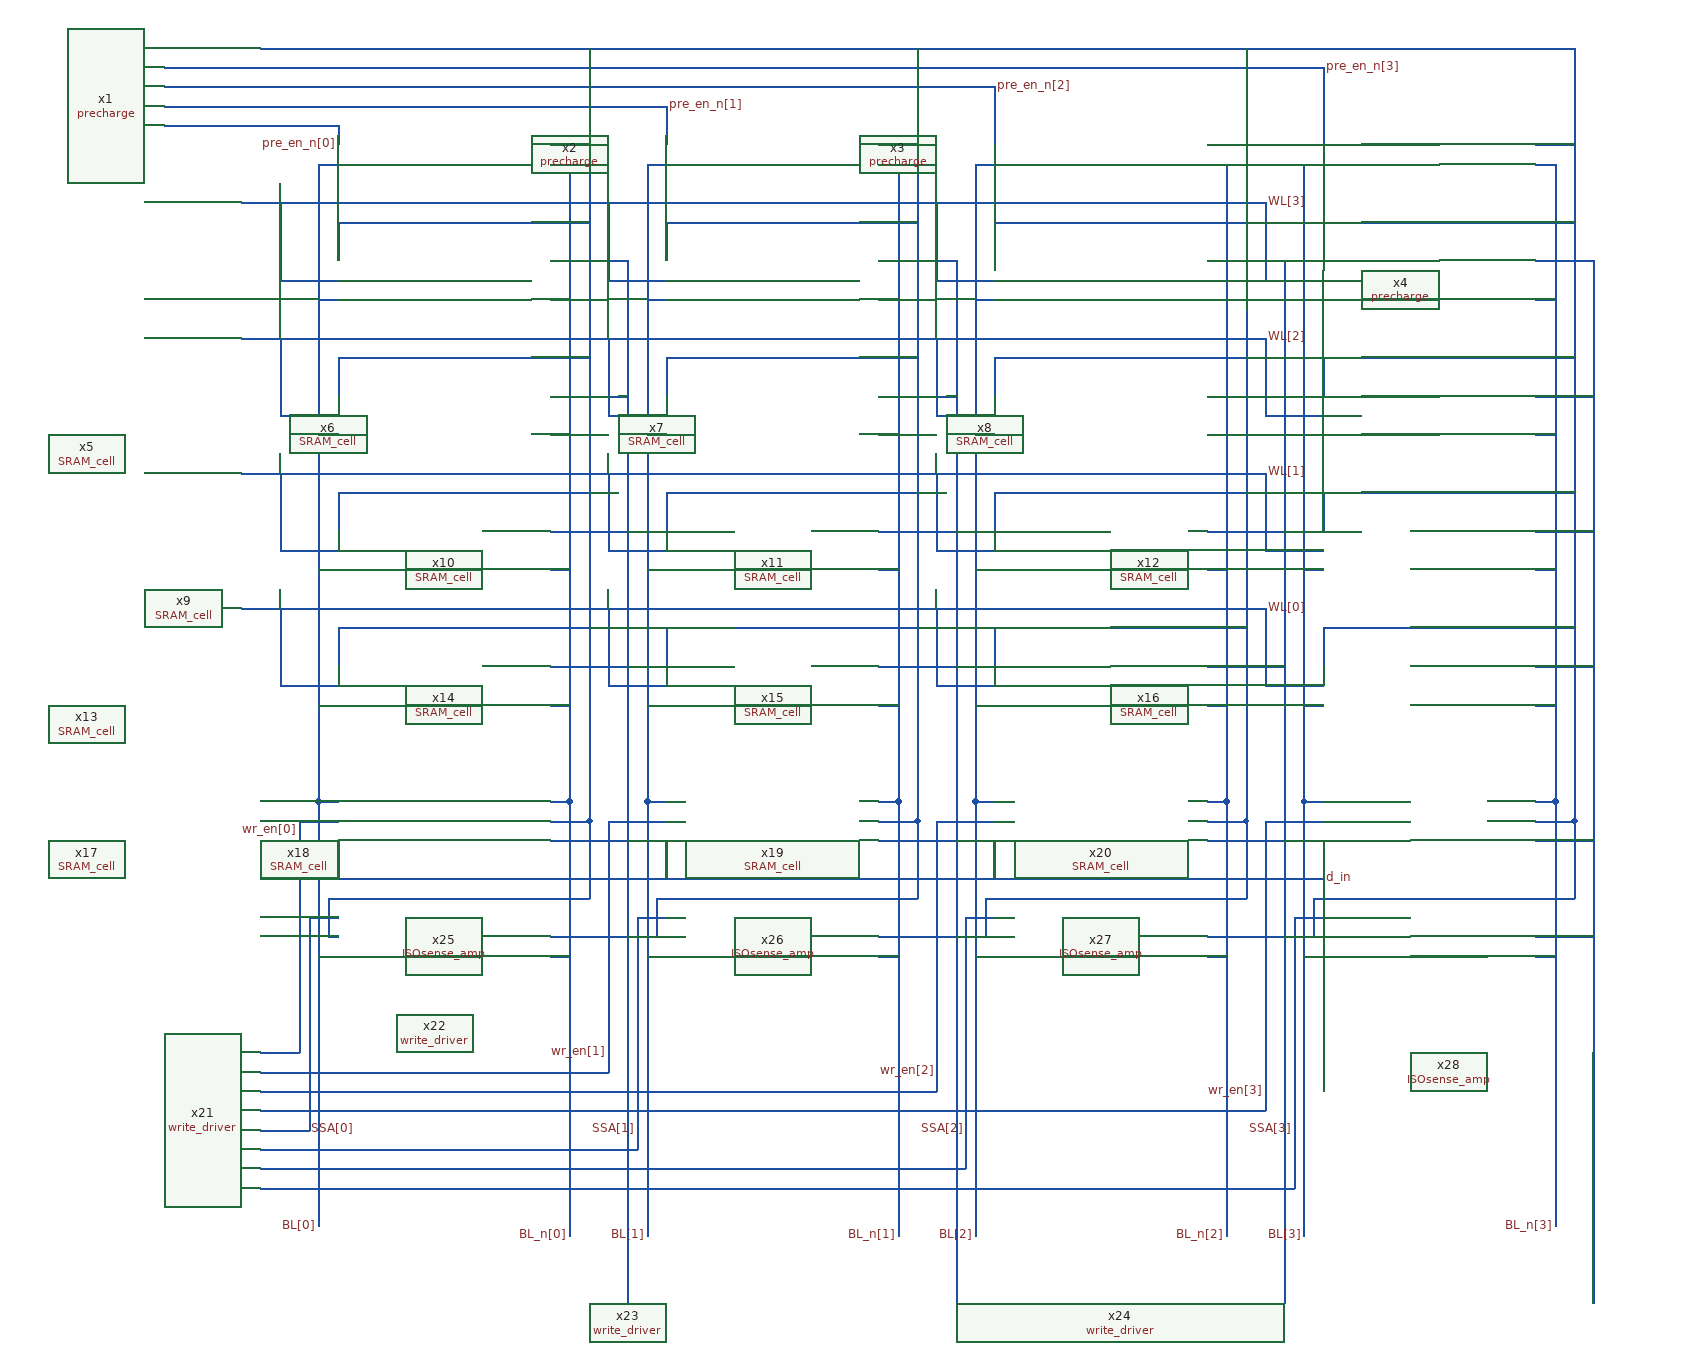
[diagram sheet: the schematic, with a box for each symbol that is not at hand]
v {xschem version=3.4.4 file_version=1.2
}
G {}
K {}
V {}
S {}
E {}
N 360 -1060 380 -1060 {
lab=BL[0]}
N 360 -920 380 -920 {
lab=BL[0]}
N 360 -780 380 -780 {
lab=BL[0]}
N 360 -640 380 -640 {
lab=BL[0]}
N 360 -500 380 -500 {
lab=BL[0]}
N 360 -400 380 -400 {
lab=BL[0]}
N 360 -1060 360 -400 {
lab=BL[0]}
N 600 -1060 620 -1060 {
lab=BL_n[0]}
N 600 -920 620 -920 {
lab=BL_n[0]}
N 600 -780 620 -780 {
lab=BL_n[0]}
N 600 -640 620 -640 {
lab=BL_n[0]}
N 600 -500 620 -500 {
lab=BL_n[0]}
N 600 -400 620 -400 {
lab=BL_n[0]}
N 620 -1060 620 -400 {
lab=BL_n[0]}
N 700 -1060 720 -1060 {
lab=BL[1]}
N 700 -920 720 -920 {
lab=BL[1]}
N 700 -780 720 -780 {
lab=BL[1]}
N 700 -640 720 -640 {
lab=BL[1]}
N 700 -500 720 -500 {
lab=BL[1]}
N 700 -400 720 -400 {
lab=BL[1]}
N 700 -1060 700 -400 {
lab=BL[1]}
N 1040 -1060 1060 -1060 {
lab=BL[2]}
N 1040 -920 1060 -920 {
lab=BL[2]}
N 1040 -780 1060 -780 {
lab=BL[2]}
N 1040 -640 1060 -640 {
lab=BL[2]}
N 1040 -500 1060 -500 {
lab=BL[2]}
N 1040 -400 1060 -400 {
lab=BL[2]}
N 1040 -1060 1040 -400 {
lab=BL[2]}
N 1380 -1060 1400 -1060 {
lab=BL[3]}
N 1380 -920 1400 -920 {
lab=BL[3]}
N 1380 -780 1400 -780 {
lab=BL[3]}
N 1380 -640 1400 -640 {
lab=BL[3]}
N 1380 -500 1400 -500 {
lab=BL[3]}
N 1380 -400 1400 -400 {
lab=BL[3]}
N 1380 -1060 1380 -400 {
lab=BL[3]}
N 940 -1060 960 -1060 {
lab=BL_n[1]}
N 940 -920 960 -920 {
lab=BL_n[1]}
N 940 -780 960 -780 {
lab=BL_n[1]}
N 940 -640 960 -640 {
lab=BL_n[1]}
N 940 -500 960 -500 {
lab=BL_n[1]}
N 940 -400 960 -400 {
lab=BL_n[1]}
N 960 -1060 960 -400 {
lab=BL_n[1]}
N 1280 -1060 1300 -1060 {
lab=BL_n[2]}
N 1280 -920 1300 -920 {
lab=BL_n[2]}
N 1280 -780 1300 -780 {
lab=BL_n[2]}
N 1280 -640 1300 -640 {
lab=BL_n[2]}
N 1280 -500 1300 -500 {
lab=BL_n[2]}
N 1280 -400 1300 -400 {
lab=BL_n[2]}
N 1300 -1060 1300 -400 {
lab=BL_n[2]}
N 1620 -1060 1640 -1060 {
lab=BL_n[3]}
N 1620 -920 1640 -920 {
lab=BL_n[3]}
N 1620 -780 1640 -780 {
lab=BL_n[3]}
N 1620 -640 1640 -640 {
lab=BL_n[3]}
N 1620 -500 1640 -500 {
lab=BL_n[3]}
N 1620 -400 1640 -400 {
lab=BL_n[3]}
N 1640 -1060 1640 -400 {
lab=BL_n[3]}
N 300 -1180 1660 -1180 {
lab=#net1}
N 600 -960 680 -960 {
lab=#net2}
N 600 -820 680 -820 {
lab=#net2}
N 600 -680 680 -680 {
lab=#net2}
N 600 -540 680 -540 {
lab=#net2}
N 600 -360 680 -360 {
lab=#net2}
N 600 -380 640 -380 {
lab=#net1}
N 600 -1080 640 -1080 {
lab=#net1}
N 380 -1000 380 -960 {
lab=#net1}
N 380 -1000 640 -1000 {
lab=#net1}
N 380 -860 380 -820 {
lab=#net1}
N 380 -860 640 -860 {
lab=#net1}
N 380 -720 380 -680 {
lab=#net1}
N 380 -720 640 -720 {
lab=#net1}
N 380 -580 380 -540 {
lab=#net1}
N 380 -580 640 -580 {
lab=#net1}
N 940 -380 980 -380 {
lab=#net1}
N 940 -1080 980 -1080 {
lab=#net1}
N 940 -960 1020 -960 {
lab=#net3}
N 940 -820 1020 -820 {
lab=#net3}
N 940 -680 1020 -680 {
lab=#net3}
N 940 -540 1020 -540 {
lab=#net3}
N 940 -360 1020 -360 {
lab=#net3}
N 720 -580 720 -540 {
lab=#net1}
N 720 -580 980 -580 {
lab=#net1}
N 720 -720 980 -720 {
lab=#net1}
N 720 -860 720 -820 {
lab=#net1}
N 720 -860 980 -860 {
lab=#net1}
N 720 -1000 720 -960 {
lab=#net1}
N 720 -1000 980 -1000 {
lab=#net1}
N 1280 -380 1320 -380 {
lab=#net1}
N 1280 -1080 1320 -1080 {
lab=#net1}
N 1280 -960 1360 -960 {
lab=#net4}
N 1280 -820 1360 -820 {
lab=#net4}
N 1280 -680 1360 -680 {
lab=#net4}
N 1280 -540 1360 -540 {
lab=#net4}
N 1280 -360 1360 -360 {
lab=#net4}
N 1620 -380 1660 -380 {
lab=#net1}
N 1620 -1080 1660 -1080 {
lab=#net1}
N 1060 -1000 1060 -960 {
lab=#net1}
N 1060 -1000 1320 -1000 {
lab=#net1}
N 1060 -860 1060 -820 {
lab=#net1}
N 1060 -860 1320 -860 {
lab=#net1}
N 1060 -720 1060 -680 {
lab=#net1}
N 1060 -720 1320 -720 {
lab=#net1}
N 1060 -580 1060 -540 {
lab=#net1}
N 1060 -580 1320 -580 {
lab=#net1}
N 1620 -960 1680 -960 {
lab=#net5}
N 1620 -820 1680 -820 {
lab=#net5}
N 1620 -680 1680 -680 {
lab=#net5}
N 1620 -540 1680 -540 {
lab=#net5}
N 1620 -360 1680 -360 {
lab=#net5}
N 1400 -580 1400 -540 {
lab=#net1}
N 1400 -580 1660 -580 {
lab=#net1}
N 1400 -720 1400 -680 {
lab=#net1}
N 1400 -720 1660 -720 {
lab=#net1}
N 1400 -860 1400 -820 {
lab=#net1}
N 1400 -860 1660 -860 {
lab=#net1}
N 1400 -1000 1400 -960 {
lab=#net1}
N 1400 -1000 1660 -1000 {
lab=#net1}
N 660 -660 720 -660 {
lab=WL[1]}
N 660 -740 660 -660 {
lab=WL[1]}
N 320 -660 380 -660 {
lab=WL[1]}
N 320 -740 320 -660 {
lab=WL[1]}
N 720 -720 720 -680 {
lab=#net1}
N 1000 -660 1060 -660 {
lab=WL[1]}
N 1000 -740 1000 -660 {
lab=WL[1]}
N 1340 -660 1400 -660 {
lab=WL[1]}
N 1340 -740 1340 -660 {
lab=WL[1]}
N 1340 -520 1400 -520 {
lab=WL[0]}
N 1340 -600 1340 -520 {
lab=WL[0]}
N 1000 -520 1060 -520 {
lab=WL[0]}
N 1000 -600 1000 -520 {
lab=WL[0]}
N 660 -520 720 -520 {
lab=WL[0]}
N 660 -600 660 -520 {
lab=WL[0]}
N 320 -520 380 -520 {
lab=WL[0]}
N 320 -600 320 -520 {
lab=WL[0]}
N 320 -940 380 -940 {
lab=WL[3]}
N 320 -1020 320 -940 {
lab=WL[3]}
N 660 -940 720 -940 {
lab=WL[3]}
N 660 -1020 660 -940 {
lab=WL[3]}
N 1000 -940 1060 -940 {
lab=WL[3]}
N 1000 -1020 1000 -940 {
lab=WL[3]}
N 1340 -940 1400 -940 {
lab=WL[3]}
N 1340 -1020 1340 -940 {
lab=WL[3]}
N 320 -800 380 -800 {
lab=WL[2]}
N 320 -880 320 -800 {
lab=WL[2]}
N 660 -800 720 -800 {
lab=WL[2]}
N 660 -880 660 -800 {
lab=WL[2]}
N 1000 -800 1060 -800 {
lab=WL[2]}
N 1000 -880 1000 -800 {
lab=WL[2]}
N 1340 -800 1400 -800 {
lab=WL[2]}
N 1340 -880 1340 -800 {
lab=WL[2]}
N 280 -1020 1340 -1020 {
lab=WL[3]}
N 280 -880 1340 -880 {
lab=WL[2]}
N 280 -740 1340 -740 {
lab=WL[1]}
N 280 -600 1340 -600 {
lab=WL[0]}
N 720 -1120 720 -1080 {
lab=pre_en_n[1]}
N 200 -1120 720 -1120 {
lab=pre_en_n[1]}
N 380 -1100 380 -1080 {
lab=pre_en_n[0]}
N 200 -1100 380 -1100 {
lab=pre_en_n[0]}
N 1060 -1140 1060 -1080 {
lab=pre_en_n[2]}
N 200 -1140 1060 -1140 {
lab=pre_en_n[2]}
N 1400 -1160 1400 -1080 {
lab=pre_en_n[3]}
N 200 -1160 1400 -1160 {
lab=pre_en_n[3]}
N 380 -360 380 -320 {
lab=d_in}
N 720 -360 720 -320 {
lab=d_in}
N 1060 -360 1060 -320 {
lab=d_in}
N 1400 -360 1400 -320 {
lab=d_in}
N 310 -320 1400 -320 {
lab=d_in}
N 300 -320 310 -320 {
lab=d_in}
N 340 -380 380 -380 {
lab=wr_en[0]}
N 340 -380 340 -300 {
lab=wr_en[0]}
N 660 -380 720 -380 {
lab=wr_en[1]}
N 660 -380 660 -280 {
lab=wr_en[1]}
N 1000 -380 1060 -380 {
lab=wr_en[2]}
N 1340 -380 1400 -380 {
lab=wr_en[3]}
N 1020 -960 1020 -220 {
lab=#net3}
N 1360 -960 1360 -220 {
lab=#net4}
N 1680 -960 1680 -220 {
lab=#net5}
N 1340 -380 1340 -240 {
lab=wr_en[3]}
N 680 -960 680 -220 {
lab=#net2}
N 360 -400 360 -180 {
lab=BL[0]}
N 620 -400 620 -180 {
lab=BL_n[0]}
N 700 -400 700 -180 {
lab=BL[1]}
N 960 -400 960 -180 {
lab=BL_n[1]}
N 1040 -400 1040 -180 {
lab=BL[2]}
N 1300 -400 1300 -180 {
lab=BL_n[2]}
N 1380 -400 1380 -180 {
lab=BL[3]}
N 1640 -400 1640 -180 {
lab=BL_n[3]}
N 1660 -1180 1660 -380 {
lab=#net1}
N 1320 -1180 1320 -380 {
lab=#net1}
N 980 -1180 980 -380 {
lab=#net1}
N 640 -1180 640 -380 {
lab=#net1}
N 640 -380 640 -300 {
lab=#net1}
N 370 -300 640 -300 {
lab=#net1}
N 370 -300 370 -260 {
lab=#net1}
N 370 -260 380 -260 {
lab=#net1}
N 980 -380 980 -300 {
lab=#net1}
N 710 -300 980 -300 {
lab=#net1}
N 710 -300 710 -260 {
lab=#net1}
N 710 -260 720 -260 {
lab=#net1}
N 1320 -380 1320 -300 {
lab=#net1}
N 1050 -300 1320 -300 {
lab=#net1}
N 1050 -300 1050 -260 {
lab=#net1}
N 1050 -260 1060 -260 {
lab=#net1}
N 1660 -380 1660 -300 {
lab=#net1}
N 1390 -300 1660 -300 {
lab=#net1}
N 1390 -300 1390 -260 {
lab=#net1}
N 1390 -260 1400 -260 {
lab=#net1}
N 360 -240 380 -240 {
lab=BL[0]}
N 600 -240 620 -240 {
lab=BL_n[0]}
N 700 -240 720 -240 {
lab=BL[1]}
N 940 -240 960 -240 {
lab=BL_n[1]}
N 1040 -240 1060 -240 {
lab=BL[2]}
N 1280 -240 1300 -240 {
lab=BL_n[2]}
N 1380 -240 1400 -240 {
lab=BL[3]}
N 1620 -240 1640 -240 {
lab=BL_n[3]}
N 1620 -260 1680 -260 {
lab=#net5}
N 660 -280 660 -120 {
lab=wr_en[1]}
N 300 -120 660 -120 {
lab=wr_en[1]}
N 600 -260 680 -260 {
lab=#net2}
N 940 -260 1020 -260 {
lab=#net3}
N 1000 -380 1000 -280 {
lab=wr_en[2]}
N 1280 -260 1360 -260 {
lab=#net4}
N 1000 -280 1000 -100 {
lab=wr_en[2]}
N 300 -100 1000 -100 {
lab=wr_en[2]}
N 1340 -240 1340 -80 {
lab=wr_en[3]}
N 300 -80 1340 -80 {
lab=wr_en[3]}
N 340 -300 340 -140 {
lab=wr_en[0]}
N 300 -140 340 -140 {
lab=wr_en[0]}
N 350 -280 380 -280 {
lab=SSA[0]}
N 350 -280 350 -60 {
lab=SSA[0]}
N 300 -60 350 -60 {
lab=SSA[0]}
N 690 -280 720 -280 {
lab=SSA[1]}
N 690 -280 690 -40 {
lab=SSA[1]}
N 300 -40 690 -40 {
lab=SSA[1]}
N 1030 -280 1060 -280 {
lab=SSA[2]}
N 1030 -280 1030 -20 {
lab=SSA[2]}
N 300 -20 1030 -20 {
lab=SSA[2]}
N 1370 -280 1400 -280 {
lab=SSA[3]}
N 1370 -280 1370 0 {
lab=SSA[3]}
N 300 -0 1370 0 {
lab=SSA[3]}
N 360 -180 360 40 {
lab=BL[0]}
N 620 -180 620 50 {
lab=BL_n[0]}
N 960 -180 960 50 {
lab=BL_n[1]}
N 700 -180 700 50 {
lab=BL[1]}
N 1040 -180 1040 50 {
lab=BL[2]}
N 1380 -180 1380 50 {
lab=BL[3]}
N 1640 -180 1640 40 {
lab=BL_n[3]}
N 1300 -180 1300 50 {
lab=BL_n[2]}
N 680 -220 680 120 {}
N 1020 -220 1020 120 {}
N 1360 -220 1360 120 {}
N 1680 -220 1680 120 {}
C {lab_pin.sym} 1400 -1160 0 1 {name=p1 sig_type=std_logic lab=pre_en_n[3]}
C {lab_pin.sym} 1060 -1140 0 1 {name=p2 sig_type=std_logic lab=pre_en_n[2]}
C {lab_pin.sym} 720 -1120 0 1 {name=p3 sig_type=std_logic lab=pre_en_n[1]}
C {lab_pin.sym} 380 -1080 0 0 {name=p4 sig_type=std_logic lab=pre_en_n[0]}
C {lab_pin.sym} 1340 -1020 0 1 {name=p5 sig_type=std_logic lab=WL[3]}
C {lab_pin.sym} 1340 -880 0 1 {name=p6 sig_type=std_logic lab=WL[2]}
C {lab_pin.sym} 1340 -740 0 1 {name=p7 sig_type=std_logic lab=WL[1]}
C {lab_pin.sym} 1340 -600 0 1 {name=p8 sig_type=std_logic lab=WL[0]}
C {lab_pin.sym} 360 40 0 0 {name=p9 sig_type=std_logic lab=BL[0]}
C {lab_pin.sym} 620 50 0 0 {name=p10 sig_type=std_logic lab=BL_n[0]}
C {lab_pin.sym} 700 50 0 0 {name=p11 sig_type=std_logic lab=BL[1]}
C {lab_pin.sym} 960 50 0 0 {name=p12 sig_type=std_logic lab=BL_n[1]}
C {lab_pin.sym} 1040 50 0 0 {name=p13 sig_type=std_logic lab=BL[2]}
C {lab_pin.sym} 1300 50 0 0 {name=p14 sig_type=std_logic lab=BL_n[2]}
C {lab_pin.sym} 1380 50 0 0 {name=p15 sig_type=std_logic lab=BL[3]}
C {lab_pin.sym} 1640 40 0 0 {name=p16 sig_type=std_logic lab=BL_n[3]}
C {lab_pin.sym} 1400 -320 0 1 {name=p17 sig_type=std_logic lab=d_in}
C {lab_pin.sym} 340 -370 0 0 {name=p18 sig_type=std_logic lab=wr_en[0]}
C {lab_pin.sym} 660 -140 0 0 {name=p19 sig_type=std_logic lab=wr_en[1]}
C {lab_pin.sym} 1000 -120 0 0 {name=p20 sig_type=std_logic lab=wr_en[2]}
C {lab_pin.sym} 1340 -100 0 0 {name=p21 sig_type=std_logic lab=wr_en[3]}
C {EE431_FINALPROJECT/proj_SRAM/precharge.sym} 200 -860 0 0 {name=x1}
C {EE431_FINALPROJECT/proj_SRAM/precharge.sym} 540 -860 0 0 {name=x2}
C {EE431_FINALPROJECT/proj_SRAM/precharge.sym} 880 -860 0 0 {name=x3}
C {EE431_FINALPROJECT/proj_SRAM/precharge.sym} 1220 -860 0 0 {name=x4}
C {EE431_FINALPROJECT/proj_SRAM/SRAM_cell.sym} 120 -760 0 0 {name=x5}
C {EE431_FINALPROJECT/proj_SRAM/SRAM_cell.sym} 460 -760 0 0 {name=x6}
C {EE431_FINALPROJECT/proj_SRAM/SRAM_cell.sym} 800 -760 0 0 {name=x7}
C {EE431_FINALPROJECT/proj_SRAM/SRAM_cell.sym} 1140 -760 0 0 {name=x8}
C {EE431_FINALPROJECT/proj_SRAM/SRAM_cell.sym} 120 -620 0 0 {name=x9}
C {EE431_FINALPROJECT/proj_SRAM/SRAM_cell.sym} 460 -620 0 0 {name=x10}
C {EE431_FINALPROJECT/proj_SRAM/SRAM_cell.sym} 800 -620 0 0 {name=x11}
C {EE431_FINALPROJECT/proj_SRAM/SRAM_cell.sym} 1140 -620 0 0 {name=x12}
C {EE431_FINALPROJECT/proj_SRAM/SRAM_cell.sym} 120 -480 0 0 {name=x13}
C {EE431_FINALPROJECT/proj_SRAM/SRAM_cell.sym} 460 -480 0 0 {name=x14}
C {EE431_FINALPROJECT/proj_SRAM/SRAM_cell.sym} 800 -480 0 0 {name=x15}
C {EE431_FINALPROJECT/proj_SRAM/SRAM_cell.sym} 1140 -480 0 0 {name=x16}
C {EE431_FINALPROJECT/proj_SRAM/SRAM_cell.sym} 120 -340 0 0 {name=x17}
C {EE431_FINALPROJECT/proj_SRAM/SRAM_cell.sym} 460 -340 0 0 {name=x18}
C {EE431_FINALPROJECT/proj_SRAM/SRAM_cell.sym} 800 -340 0 0 {name=x19}
C {EE431_FINALPROJECT/proj_SRAM/SRAM_cell.sym} 1140 -340 0 0 {name=x20}
C {EE431_FINALPROJECT/proj_SRAM/write_driver.sym} 140 -160 0 0 {name=x21}
C {EE431_FINALPROJECT/proj_SRAM/write_driver.sym} 480 -160 0 0 {name=x22}
C {EE431_FINALPROJECT/proj_SRAM/write_driver.sym} 820 -160 0 0 {name=x23}
C {EE431_FINALPROJECT/proj_SRAM/write_driver.sym} 1160 -160 0 0 {name=x24}
C {EE431_FINALPROJECT/proj_SRAM/ISOsense_amp.sym} 500 -240 0 0 {name=x25}
C {EE431_FINALPROJECT/proj_SRAM/ISOsense_amp.sym} 840 -240 0 0 {name=x26}
C {EE431_FINALPROJECT/proj_SRAM/ISOsense_amp.sym} 1180 -240 0 0 {name=x27}
C {EE431_FINALPROJECT/proj_SRAM/ISOsense_amp.sym} 1520 -240 0 0 {name=x28}
C {lab_pin.sym} 350 -60 0 1 {name=p22 sig_type=std_logic lab=SSA[0]}
C {lab_pin.sym} 690 -60 0 0 {name=p23 sig_type=std_logic lab=SSA[1]}
C {lab_pin.sym} 1030 -60 0 0 {name=p24 sig_type=std_logic lab=SSA[2]}
C {lab_pin.sym} 1370 -60 0 0 {name=p25 sig_type=std_logic lab=SSA[3]}
